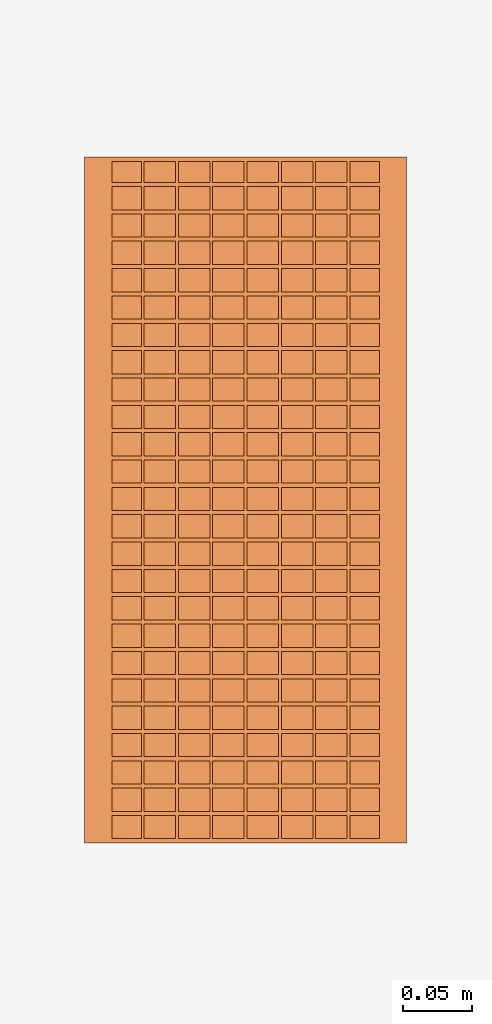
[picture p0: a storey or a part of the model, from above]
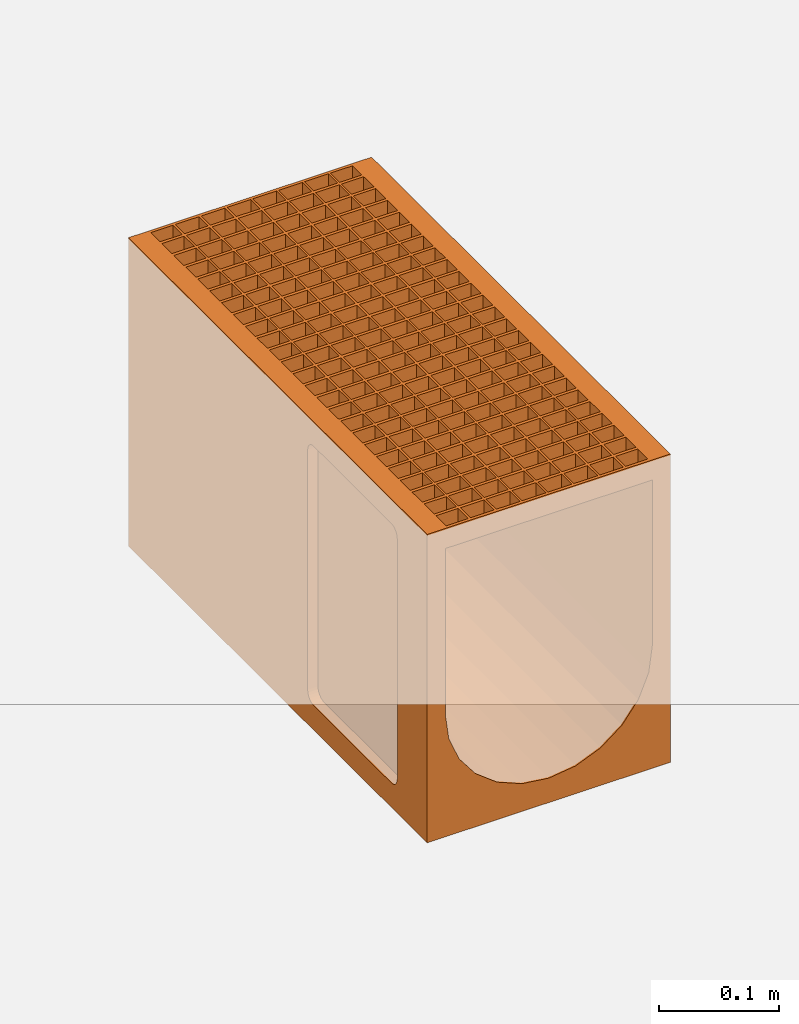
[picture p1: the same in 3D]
Properties of the parts of a building model (IFC2X3)

# File
Description: ViewDefinition [CoordinationView]
File name: 24214 - No 10.1J Constant Depth Channel - 500mm LG - Invert Depth 290mm.ifc
Time: 2013-10-16T12:49:49
Written by: Autodesk Revit 2013
Made in: 20120221_2030(x64)

# IfcProject, Project Number
LongName: Project Name; Phase: Project Status

# IfcSite, Default
RefLatitude: 42, 21, 30, 344238; RefLongitude: -71, -3, -35, -194702; RefElevation: 0 mm

# IfcBuilding
Pset_BuildingCommon - NumberOfStoreys: 1
Other - Client Name: Owner; Project Address: ## Street City, State Zip; Project Status: Project Status; Project Issue Date: Issue Date; Project Number: Project Number; Project Name: Project Name

# IfcBuildingStorey, Level 1
LongName: Level 1; Elevation: 0 mm
Constraints - Elevation Base: 0; Elevation: 0 mm
Graphics - Line Weight: 1; Color: 0; Line Pattern: Center; Symbol at End 1 Default: no; Symbol at End 2 Default: yes; Symbol: M_Level Head - Circle: M_Level Head - Circle
Identity Data - Building Story: yes; Name: Level 1; Structural: no
Dimensions - Computation Height: 0 mm

# IfcBuildingElementProxy: 24214 - No 10.1J Constant Depth Channel - 500mm LG - Invert Depth 290mm, Civil-Drainage-Channel-ACO-MultiDrain-M200DS-Channel-System:24214 - No 10.1J Constant Depth Channel - 500mm LG - Invert Depth 290mm:24214 - No 10.1J Constant Depth Channel - 500mm LG - Invert Depth 290mm:1152340
In: Level 1
Material: Vienite® Synthetic Resin Concrete
Construction - 23219 - Universal Endcap (Female End): no; 13449 - Grating - Mesh - Stainless Steel - 500mm Long: no; 23219 - Universal Endcap (Male End): no; 13448 - Grating - Mesh - Stainless Steel - 1000mm Long: no; 23410_Sump Unit: no; Shallow Depth Channel with seal: no; Shallow Depth Channel: no; Grating_1000mm: no; Constant Depth Channel_1000: no; Grating_500mm: yes; Constant Depth Channel_500: yes
Dimensions - Custom_Value_Length: 0 mm; EndCap Position: 500 mm; Length: 1000 mm; FloorCut_Length: -500 mm; Volume: 9671112 mm3; FloorCut_Width: 235 mm; EndCap_Height: 315 mm; Depth: 315 mm; FloorCut_HorPosition: 117.5 mm; InvDepth: 190 mm; FloorCut_Depth: 315 mm
Phasing - Phase Created: New Construction
Constraints - Moves With Nearby Elements: no; Level: Level: Level 1
Pset_BuildingElementProxyCommon - Reference: 24214 - No 10.1J Constant Depth Channel - 500mm LG - Invert Depth 290mm
Data - Product Dimensions: 500mm x 235mm x 315mm (LxWxH); Concrete Surround Volume - Load Class A 15 - Concrete Pavement: 0.12m³/m; Hydraulic Performance: http://www.aco.co.uk/download.php?id=173; Product Weight: 20.9 Kg; Concrete Surround Volume - Load Class D 400 - Concrete Pavement: 0.26m³/m; Product Standard: BS EN 1433:2002, CE marked; ACO Hydraulic Design Software: http://www.acodesign.co.uk; Installation - Concrete Grade: Refer to brochure; Concrete Surround Volume - Load Class B 125 - C 250 - Concrete Pavement: 0.19m³/m; Invert Depth: 290mm; Channel C.S.A: 0.043m²; Load Class: A 15 - D 400
Identity Data - Watermarked With: BIM Manager Premium Suite; Assembly Description: Rain Water Drainage; Fax: +44 (0)1462 815895; Maintenance guidelines: http://www.aco.co.uk/download.php?id=173; Product Code: 24214; Product Page URL: http://www.aco.co.uk/product_detail.php?id=15; e-mail Technical: technical@aco.co.uk; Product brochure: http://www.aco.co.uk/download.php?id=173; Installation guidelines: http://www.aco.co.uk/download.php?id=173; Manufacturer: ACO Technologies plc - ACO Water Management Division; Watermark 2: This file is water marked and users are prohibited to reproduce, adapt, distribute this information; Model Description: Channel drainage system; e-mail Sales: customersupport@aco.co.uk; OmniClass Title: Rainwater Removal; OmniClass Number: 23.70.50.24; Cost: 0; Assembly Code: D2040; Address: ACO Business Park, Hitchin Road, Shefford, Bedfordshire, United Kingdom SG17 5TE; Type Comments: ACO MultiDrain M200DS 10.1J Constant Depth Channel 500mm Long; Model: ACO MultiDrain MD - M200DS; Telephone: +44 (0)1462 816666; Watermarked By: www.aco.co.uk; URL: www.aco.co.uk; Watermark 1: This file is the property of ACO Technologies PLC; Price: POA - contact ACO
Model Properties - Grating Product code 13449: Load Class C250 - Mesh Stainless Steel Grade 304 13449DL 500mm long - 23x17mm slot - Intake area 154100mm²/m - 6.0kg; End Cap Product code 23219: No 306 Universal End Cap - 235mm wide x 365mm long - Spigot Ø160mm x 75mm long - Silver - Polypropylene - 0.4kg; Grating Product code 13448: N/A
Green Building Properties - Edge Rail Recycled Material Content: Between 40% - 90%; Channel Recyclable: Fully recyclable; Edge Rail Recyclable: Fully recyclable; Channel Recycled Material Content: 20% minimum
General - TagNumber: 0; SerialNumber: 0
Other - Revision: 1; CreatedBy: www.aco.co.uk
Materials and Finishes - Channel Colour: Brown; Edge Rail Colour: Self; Channel Material: Vienite® Synthetic Resin Concrete; Edge Rail Material: Stainless Steel Grade 304

# IfcOpeningElement: Recess
In: Level 1
Phasing - Phase Created: New Construction
Dimensions - Volume: 9962987500 mm3; Thickness: 400 mm; Area: 25000000 mm2; Perimeter: 20000 mm
Constraints - Level: Level: Level 1; Height Offset From Level: 0 mm; Room Bounding: yes; Related to Mass: no
Structural - Structural: no; Enable Analytical Model: no
Analytical Properties - Thermal Resistance (R): 0.477897; Roughness: 1; Thermal mass: 543920; Heat Transfer Coefficient (U): 2.0925; Absorptance: 0.1
Construction - Function: 0; Default Thickness: 400 mm
Materials and Finishes - Structural Material: Earth
Graphics - Coarse Scale Fill Color: 0

# IfcSlab: Floor:Generic Floor - 400mm, Floor:Generic Floor - 400mm:193825
In: Level 1
PredefinedType: FLOOR; Material: Earth 400 mm
Phasing - Phase Created: New Construction
Dimensions - Volume: 9962987500 mm3; Thickness: 400 mm; Area: 25000000 mm2; Perimeter: 20000 mm
Constraints - Level: Level: Level 1; Height Offset From Level: 0 mm; Room Bounding: yes; Related to Mass: no
Structural - Structural: no; Enable Analytical Model: no
Pset_SlabCommon - Reference: Generic Floor - 400mm; IsExternal: no; LoadBearing: yes
Analytical Properties - Thermal Resistance (R): 0.477897; Roughness: 1; Thermal mass: 543920; Heat Transfer Coefficient (U): 2.0925; Absorptance: 0.1
Construction - Function: 0; Default Thickness: 400 mm
Materials and Finishes - Structural Material: Earth
Graphics - Coarse Scale Fill Color: 0
